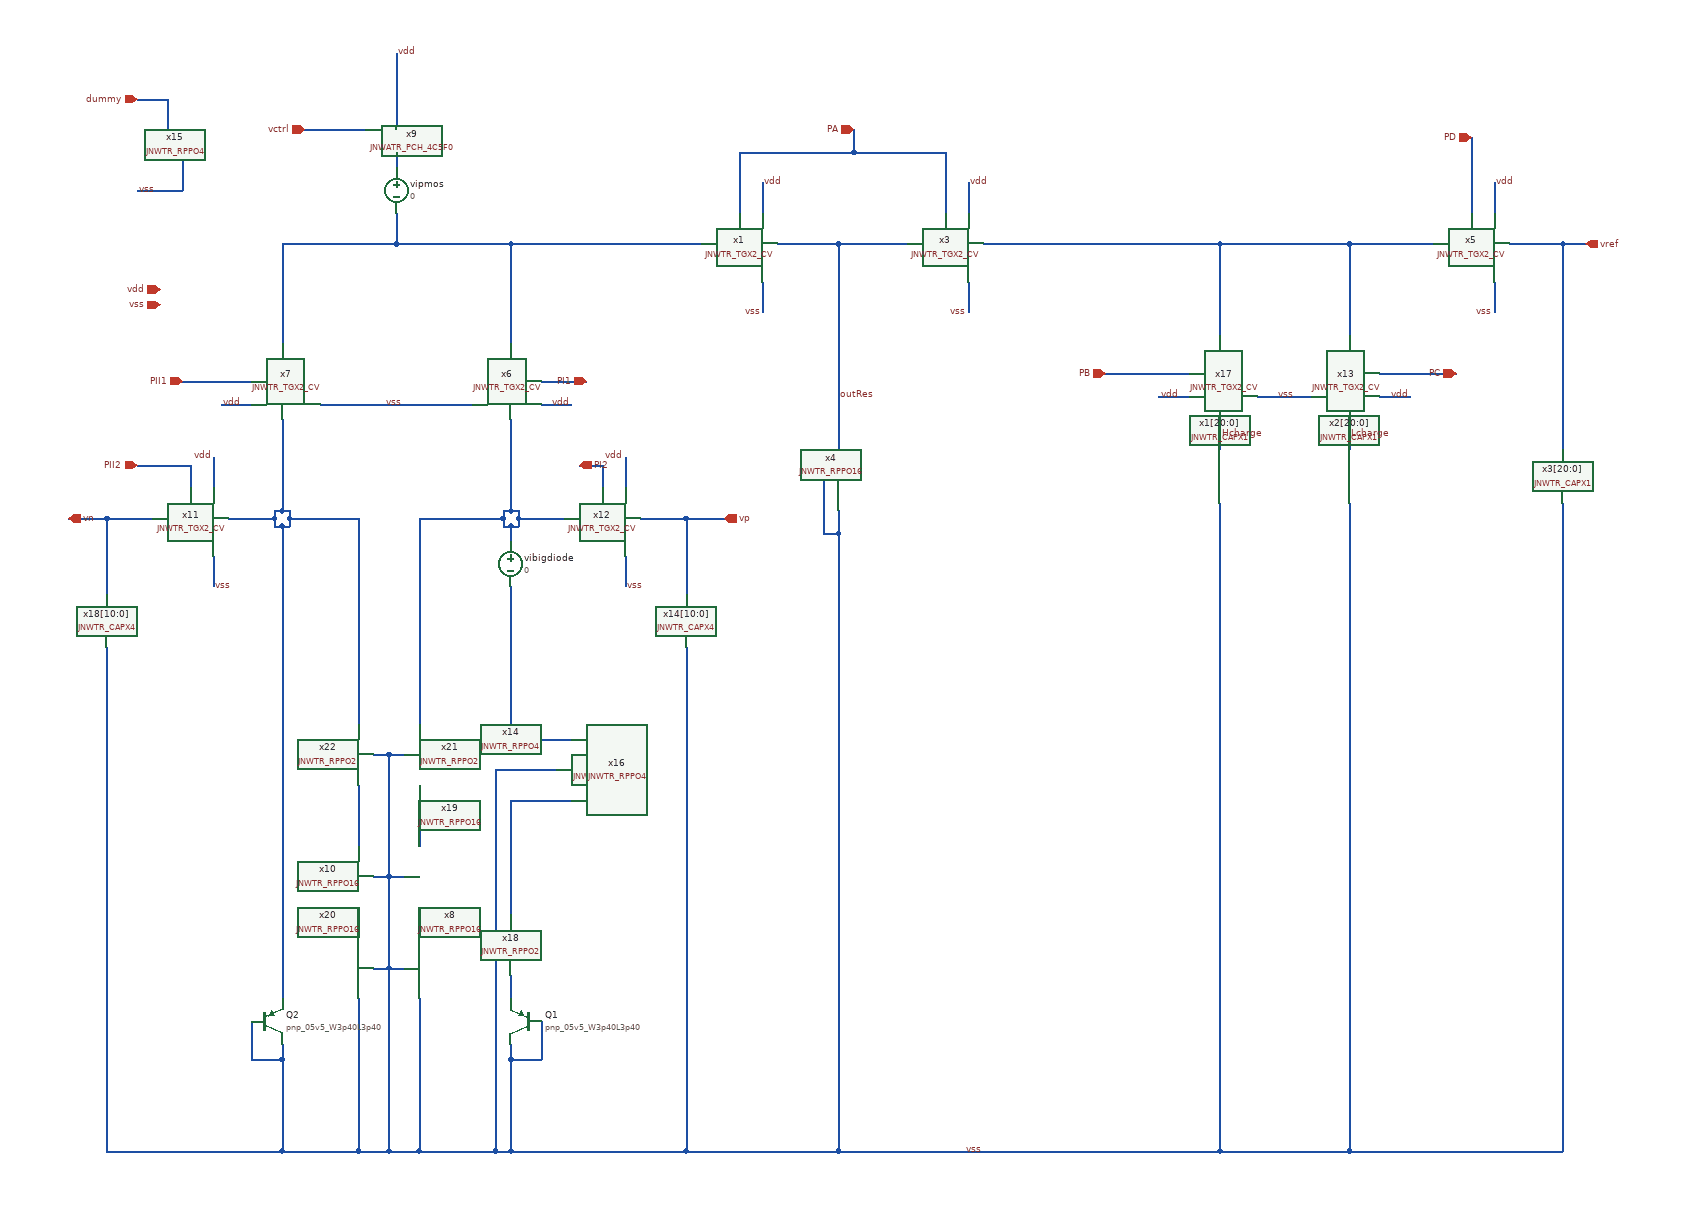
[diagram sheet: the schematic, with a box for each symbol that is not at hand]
v {xschem version=3.4.5 file_version=1.2
}
G {}
K {}
V {}
S {}
E {}
N 1370 -1540 1370 -1270 {
lab=outRes}
N 1350 -1230 1350 -1160 {
lab=vss}
N 1350 -1160 1370 -1160 {
lab=vss}
N 1370 -1190 1370 -1160 {
lab=vss}
N 1270 -1490 1270 -1450 {
lab=vss}
N 1270 -1620 1270 -1580 {
lab=vdd}
N 1240 -1660 1240 -1580 {
lab=PA}
N 1540 -1490 1540 -1450 {
lab=vss}
N 1540 -1620 1540 -1580 {
lab=vdd}
N 1510 -1660 1510 -1580 {
lab=PA}
N 1920 -1340 1990 -1340 {
lab=vss}
N 1790 -1340 1830 -1340 {
lab=vdd}
N 1720 -1370 1830 -1370 {
lab=PB}
N 2080 -1370 2180 -1370 {
lab=PC}
N 2080 -1340 2120 -1340 {
lab=vdd}
N 2230 -1490 2230 -1450 {
lab=vss}
N 2230 -1620 2230 -1580 {
lab=vdd}
N 2200 -1680 2200 -1580 {
lab=PD}
N 2320 -1540 2320 -1270 {
lab=vref}
N 560 -1330 600 -1330 {
lab=vdd}
N 980 -1360 1040 -1360 {
lab=PI1}
N 980 -1330 1020 -1330 {
lab=vdd}
N 690 -1330 890 -1330 {
lab=vss}
N 930 -1180 930 -1170 {
lab=#net1}
N 940 -1190 950 -1190 {
lab=#net1}
N 650 -1180 650 -1170 {
lab=#net2}
N 640 -1170 650 -1170 {
lab=#net2}
N 640 -1190 650 -1190 {
lab=#net2}
N 950 -1180 950 -1170 {
lab=#net1}
N 1170 -1180 1220 -1180 {
lab=vp}
N 1170 -1180 1170 -1080 {
lab=vp}
N 1370 -1160 1370 -350 {
lab=vss}
N 650 -1190 650 -1180 {
lab=#net2}
N 930 -1190 930 -1180 {
lab=#net1}
N 630 -1170 640 -1170 {
lab=#net2}
N 640 -1170 640 -550 {
lab=#net2}
N 650 -1180 740 -1180 {
lab=#net2}
N 360 -1180 410 -1180 {
lab=vn}
N 410 -1180 410 -1080 {
lab=vn}
N 630 -1180 630 -1170 {
lab=#net2}
N 410 -1010 410 -350 {
lab=vss}
N 2040 -350 2320 -350 {
lab=vss}
N 2320 -1200 2320 -350 {
lab=vss}
N 2040 -1200 2040 -350 {
lab=vss}
N 1870 -350 2040 -350 {
lab=vss}
N 1870 -1200 1870 -350 {
lab=vss}
N 1370 -350 1870 -350 {
lab=vss}
N 1170 -1010 1170 -350 {
lab=vss}
N 940 -350 1170 -350 {
lab=vss}
N 1170 -350 1370 -350 {
lab=vss}
N 940 -470 940 -350 {
lab=vss}
N 640 -470 640 -350 {
lab=vss}
N 410 -350 640 -350 {
lab=vss}
N 600 -520 600 -470 {
lab=vss}
N 600 -470 640 -470 {
lab=vss}
N 980 -520 980 -470 {
lab=vss}
N 940 -470 980 -470 {
lab=vss}
N 940 -490 940 -470 {
lab=vss}
N 1090 -1130 1090 -1090 {
lab=vss}
N 550 -1130 550 -1090 {
lab=vss}
N 1090 -1260 1090 -1220 {
lab=vdd}
N 550 -1260 550 -1220 {
lab=vdd}
N 670 -1690 750 -1690 {
lab=vctrl}
N 790 -1790 790 -1690 {
lab=vdd}
N 520 -1250 520 -1220 {
lab=PII2}
N 450 -1250 520 -1250 {
lab=PII2}
N 1030 -1250 1060 -1250 {
lab=PI2}
N 2320 -1540 2350 -1540 {
lab=vref}
N 1390 -1660 1510 -1660 {
lab=PA}
N 1390 -1690 1390 -1660 {
lab=PA}
N 1240 -1660 1390 -1660 {
lab=PA}
N 510 -1360 600 -1360 {
lab=PII1}
N 450 -1730 490 -1730 {
lab=dummy}
N 490 -1730 490 -1690 {
lab=dummy}
N 510 -1650 510 -1610 {
lab=vss}
N 450 -1610 510 -1610 {
lab=vss}
N 640 -490 640 -470 {
lab=vss}
N 820 -1180 930 -1180 {
lab=#net1}
N 940 -1170 950 -1170 {
lab=#net1}
N 920 -350 940 -350 {
lab=vss}
N 790 -1660 790 -1640 {
lab=#net3}
N 790 -1580 790 -1540 {
lab=#net4}
N 640 -1540 790 -1540 {
lab=#net4}
N 940 -1170 940 -1150 {
lab=#net1}
N 930 -1170 940 -1170 {
lab=#net1}
N 940 -810 940 -660 {
lab=#net5}
N 940 -580 940 -550 {
lab=#net6}
N 740 -550 740 -350 {
lab=vss}
N 820 -550 820 -350 {
lab=vss}
N 780 -590 800 -590 {
lab=vss}
N 780 -590 780 -350 {
lab=vss}
N 760 -590 780 -590 {
lab=vss}
N 740 -670 740 -630 {
lab=#net7}
N 820 -670 820 -630 {
lab=#net8}
N 780 -710 800 -710 {
lab=vss}
N 760 -710 780 -710 {
lab=vss}
N 780 -710 780 -590 {
lab=vss}
N 780 -870 800 -870 {
lab=vss}
N 780 -870 780 -710 {
lab=vss}
N 760 -870 780 -870 {
lab=vss}
N 640 -350 740 -350 {
lab=vss}
N 740 -350 780 -350 {
lab=vss}
N 780 -350 820 -350 {
lab=vss}
N 940 -1090 940 -890 {
lab=#net9}
N 820 -830 820 -750 {
lab=#net10}
N 740 -830 740 -750 {
lab=#net11}
N 820 -1180 820 -910 {
lab=#net1}
N 740 -1180 740 -910 {
lab=#net2}
N 940 -810 1020 -810 {
lab=#net5}
N 940 -890 1020 -890 {
lab=#net9}
N 920 -850 920 -350 {
lab=vss}
N 920 -850 1000 -850 {
lab=vss}
N 820 -350 920 -350 {
lab=vss}
N 2040 -1540 2150 -1540 {
lab=#net12}
N 2250 -1540 2320 -1540 {
lab=vref}
N 1370 -1540 1460 -1540 {
lab=outRes}
N 1290 -1540 1370 -1540 {
lab=outRes}
N 940 -1540 1190 -1540 {
lab=#net4}
N 640 -1540 640 -1410 {
lab=#net4}
N 940 -1540 940 -1410 {
lab=#net4}
N 790 -1540 940 -1540 {
lab=#net4}
N 940 -1310 940 -1190 {
lab=#net1}
N 930 -1190 940 -1190 {
lab=#net1}
N 950 -1180 1010 -1180 {
lab=#net1}
N 950 -1190 950 -1180 {
lab=#net1}
N 570 -1180 630 -1180 {
lab=#net2}
N 630 -1190 630 -1180 {
lab=#net2}
N 640 -1310 640 -1190 {
lab=#net2}
N 630 -1190 640 -1190 {
lab=#net2}
N 410 -1180 470 -1180 {
lab=vn}
N 1870 -1320 1870 -1270 {
lab=Hcharge}
N 2040 -1320 2040 -1270 {
lab=Lcharge}
N 1870 -1540 1870 -1420 {
lab=#net12}
N 1560 -1540 1870 -1540 {
lab=#net12}
N 2040 -1540 2040 -1420 {
lab=#net12}
N 1870 -1540 2040 -1540 {
lab=#net12}
N 1110 -1180 1170 -1180 {
lab=vp}
N 1060 -1250 1060 -1220 {
lab=PI2}
C {devices/ipin.sym} 480 -1480 0 0 {name=p1 lab=vdd}
C {devices/ipin.sym} 480 -1460 0 0 {name=p2 lab=vss
}
C {devices/lab_wire.sym} 1560 -350 0 0 {name=p4 sig_type=std_logic lab=vss
}
C {devices/lab_wire.sym} 1270 -1450 0 0 {name=p5 sig_type=std_logic lab=vss
}
C {devices/lab_wire.sym} 1270 -1620 0 1 {name=p6 sig_type=std_logic lab=vdd

}
C {devices/lab_wire.sym} 1970 -1340 0 0 {name=p7 sig_type=std_logic lab=vss
}
C {devices/lab_wire.sym} 1540 -1450 0 0 {name=p9 sig_type=std_logic lab=vss
}
C {devices/lab_wire.sym} 1540 -1620 0 1 {name=p11 sig_type=std_logic lab=vdd

}
C {devices/lab_wire.sym} 1790 -1340 0 1 {name=p12 sig_type=std_logic lab=vdd

}
C {devices/lab_wire.sym} 2120 -1340 0 0 {name=p13 sig_type=std_logic lab=vdd

}
C {devices/lab_wire.sym} 2230 -1450 0 0 {name=p14 sig_type=std_logic lab=vss
}
C {devices/lab_wire.sym} 2230 -1620 0 1 {name=p17 sig_type=std_logic lab=vdd

}
C {devices/lab_wire.sym} 800 -1330 0 0 {name=p18 sig_type=std_logic lab=vss
}
C {devices/lab_wire.sym} 560 -1330 0 1 {name=p19 sig_type=std_logic lab=vdd

}
C {devices/lab_wire.sym} 1020 -1330 0 0 {name=p20 sig_type=std_logic lab=vdd

}
C {JNW_TR_SKY130A/JNWTR_CAPX4.sym} 1170 -1020 0 0 {name=x14[10:0]}
C {JNW_TR_SKY130A/JNWTR_CAPX4.sym} 410 -1020 0 1 {name=x18[10:0]}
C {sky130_fd_pr/pnp_05v5.sym} 960 -520 0 1 {name=Q1
model=pnp_05v5_W3p40L3p40
m=8
spiceprefix=X
}
C {sky130_fd_pr/pnp_05v5.sym} 620 -520 0 0 {name=Q2
model=pnp_05v5_W3p40L3p40
m=1
spiceprefix=X
}
C {devices/lab_wire.sym} 1090 -1090 0 1 {name=p23 sig_type=std_logic lab=vss
}
C {devices/lab_wire.sym} 550 -1090 0 1 {name=p24 sig_type=std_logic lab=vss
}
C {devices/lab_wire.sym} 1090 -1260 0 0 {name=p25 sig_type=std_logic lab=vdd

}
C {devices/lab_wire.sym} 550 -1260 0 0 {name=p26 sig_type=std_logic lab=vdd

}
C {devices/ipin.sym} 670 -1690 0 0 {name=p27 lab=vctrl}
C {devices/lab_wire.sym} 790 -1790 0 1 {name=p28 sig_type=std_logic lab=vdd

}
C {devices/ipin.sym} 2200 -1680 1 0 {name=p8 lab=PD}
C {devices/ipin.sym} 1720 -1370 0 0 {name=p10 lab=PB}
C {devices/ipin.sym} 2180 -1370 2 0 {name=p15 lab=PC}
C {devices/ipin.sym} 1390 -1690 1 0 {name=p16 lab=PA}
C {devices/ipin.sym} 1030 -1250 2 1 {name=p31 lab=PI2}
C {devices/ipin.sym} 450 -1730 0 0 {name=p32 lab=dummy}
C {devices/ipin.sym} 510 -1360 0 0 {name=p33 lab=PII1}
C {devices/ipin.sym} 1040 -1360 2 0 {name=p34 lab=PI1}
C {devices/opin.sym} 2350 -1540 0 0 {name=p3 lab=vref}
C {devices/opin.sym} 1220 -1180 0 0 {name=p21 lab=vp}
C {devices/opin.sym} 360 -1180 2 0 {name=p22 lab=vn}
C {devices/ipin.sym} 450 -1250 0 0 {name=p29 lab=PII2}
C {JNW_TR_SKY130A/JNWTR_RPPO4.sym} 490 -1690 3 1 {name=x15 }
C {devices/lab_wire.sym} 450 -1610 0 1 {name=p30 sig_type=std_logic lab=vss
}
C {JNW_TR_SKY130A/JNWTR_CAPX1.sym} 1870 -1210 0 0 {name=x1[20:0]}
C {JNW_TR_SKY130A/JNWTR_CAPX1.sym} 2040 -1210 0 0 {name=x2[20:0]}
C {JNW_TR_SKY130A/JNWTR_CAPX1.sym} 2320 -1210 0 0 {name=x3[20:0]}
C {JNW_ATR_SKY130A/JNWATR_PCH_4C5F0.sym} 750 -1690 0 0 {name=x9 }
C {devices/vsource.sym} 790 -1610 0 0 {name=vipmos value=0 savecurrent=true}
C {devices/vsource.sym} 940 -1120 0 0 {name=vibigdiode value=0 savecurrent=true}
C {JNW_TR_SKY130A/JNWTR_RPPO2.sym} 940 -660 1 0 {name=x18 }
C {devices/lab_wire.sym} 1870 -1290 0 1 {name=p35 sig_type=std_logic lab=Hcharge

}
C {devices/lab_wire.sym} 2040 -1290 0 1 {name=p36 sig_type=std_logic lab=Lcharge

}
C {devices/lab_wire.sym} 1370 -1340 0 1 {name=p37 sig_type=std_logic lab=outRes

}
C {JNW_TR_SKY130A/JNWTR_RPPO16.sym} 820 -630 1 0 {name=x8 }
C {JNW_TR_SKY130A/JNWTR_RPPO16.sym} 740 -630 3 1 {name=x20 }
C {JNW_TR_SKY130A/JNWTR_RPPO4.sym} 980 -890 1 0 {name=x2 }
C {JNW_TR_SKY130A/JNWTR_RPPO4.sym} 940 -890 1 0 {name=x14 }
C {JNW_TR_SKY130A/JNWTR_RPPO4.sym} 1020 -890 1 0 {name=x16 }
C {JNW_TR_SKY130A/JNWTR_RPPO16.sym} 740 -750 3 1 {name=x10 }
C {JNW_TR_SKY130A/JNWTR_RPPO16.sym} 820 -750 1 0 {name=x19 }
C {JNW_TR_SKY130A/JNWTR_RPPO16.sym} 1370 -1270 1 0 {name=x4 }
C {JNW_TR_SKY130A/JNWTR_RPPO2.sym} 820 -910 1 0 {name=x21 }
C {JNW_TR_SKY130A/JNWTR_RPPO2.sym} 740 -830 3 0 {name=x22 }
C {JNW_TR_SKY130A/JNWTR_TGX2_CV.sym} 1180 -1540 0 0 {name=x1 }
C {JNW_TR_SKY130A/JNWTR_TGX2_CV.sym} 1450 -1540 0 0 {name=x3 }
C {JNW_TR_SKY130A/JNWTR_TGX2_CV.sym} 2140 -1540 0 0 {name=x5 }
C {JNW_TR_SKY130A/JNWTR_TGX2_CV.sym} 940 -1420 1 0 {name=x6 }
C {JNW_TR_SKY130A/JNWTR_TGX2_CV.sym} 640 -1420 3 1 {name=x7 }
C {JNW_TR_SKY130A/JNWTR_TGX2_CV.sym} 460 -1180 0 0 {name=x11 }
C {JNW_TR_SKY130A/JNWTR_TGX2_CV.sym} 1000 -1180 0 0 {name=x12 }
C {JNW_TR_SKY130A/JNWTR_TGX2_CV.sym} 2040 -1430 1 0 {name=x13 }
C {JNW_TR_SKY130A/JNWTR_TGX2_CV.sym} 1870 -1430 3 1 {name=x17 }
